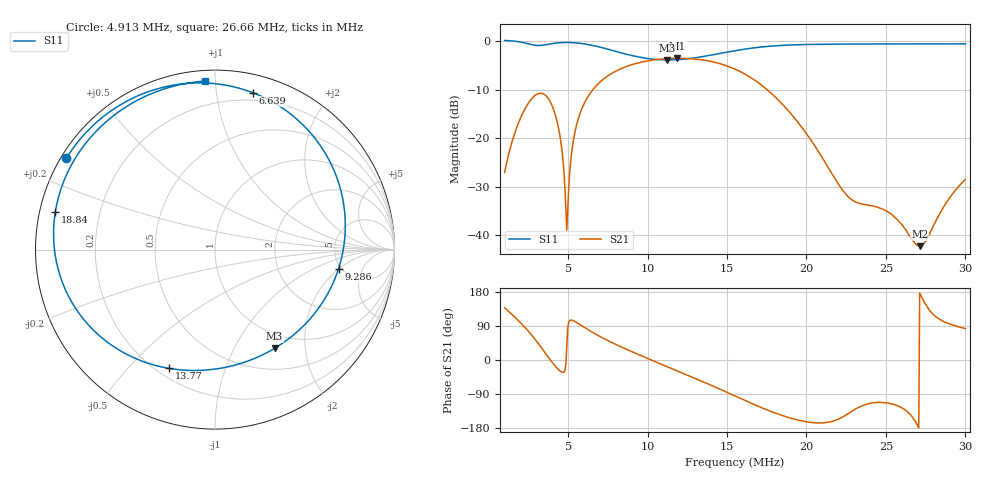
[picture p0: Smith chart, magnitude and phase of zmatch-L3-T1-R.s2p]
# HZ S RI R 50
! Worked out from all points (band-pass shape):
!   505 points, 1 MHz to 30 MHz, reference 50 ohm
!   highest |S21| = -3.50 dB at 11.88 MHz (marker M1); lowest = -42.2 dB at 27.12 MHz (marker M2)
!   |S21| within 3 dB of the highest: 7.808 MHz to 15.98 MHz (8.169 MHz wide, 68.7 % of centre)
!   lowest |S11| = -3.8 dB at 11.24 MHz (marker M3), VSWR 4.60, Z = 39.2 - j73.4 ohm
!   |S11| at or under -10 dB: nowhere
!   S12 and S22 are empty: the file has one direction only
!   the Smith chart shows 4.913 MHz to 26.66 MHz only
!   S11 on the Smith chart (normalised r, x): 4.913 MHz: 0.02, +0.28; 6.639 MHz: 0.14, +1.26; 9.286 MHz: 4.75, -1.97; 13.77 MHz: 0.25, -0.66; 18.84 MHz: 0.05, +0.12; 26.66 MHz: 0.06, +0.94
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1000000  -0.6017 0.8237  -0.0329 0.0298  0 0  0 0
1920640  0.3133 0.9368  -0.0309 0.1474  0 0  0 0
2668660  0.9283 -0.00518  0.0961 0.2327  0 0  0 0
3128980  0.4685 -0.7745  0.2115 0.197  0 0  0 0
3474220  -0.1805 -0.897  0.2623 0.1121  0 0  0 0
4107160  -0.9037 -0.3031  0.1887 -0.0404  0 0  0 0
4912720  -0.8285 0.5086  0.00941 0.00633  0 0  0 0
5833360  -0.278 0.907  -0.00278 0.1965  0 0  0 0
6638920  0.2127 0.8734  0.1112 0.3107  0 0  0 0
7904800  0.6663 0.4335  0.3539 0.3286  0 0  0 0
9285760  0.6885 -0.1066  0.566 0.1719  0 0  0 0
1.066672e7  0.4559 -0.4596  0.6449 -0.0874  0 0  0 0
1.124212e7  0.3316 -0.5504  0.6316 -0.2019  0 0  0 0
1.187506e7  0.1879 -0.6192  0.5862 -0.3213  0 0  0 0
1.377388e7  -0.2573 -0.6615  0.2903 -0.5588  0 0  0 0
1.550008e7  -0.6323 -0.4898  -0.0442 -0.5147  0 0  0 0
1.88374e7  -0.8895 0.2112  -0.1703 -0.093  0 0  0 0
2.033344e7  -0.7918 0.4866  -0.0898 -0.0239  0 0  0 0
2.51668e7  -0.2323 0.9101  -0.00704 -0.0158  0 0  0 0
2.666284e7  -0.058 0.9386  -0.00781 -0.00452  0 0  0 0
2.712316e7  -0.0068 0.9406  -0.00773 0.000414  0 0  0 0
3.000016e7  0.2835 0.8975  0.00463 0.0376  0 0  0 0
